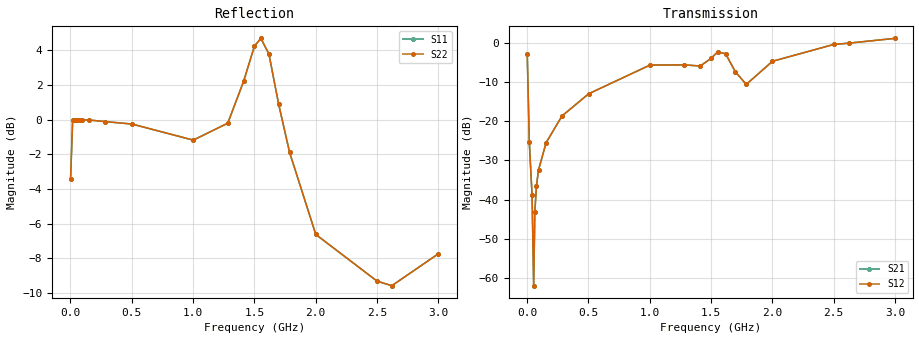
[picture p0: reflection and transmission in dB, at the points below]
!s-Parameter Generated by FASTRON Sdn. Bhd.
!FASTRON P/N : MICC-150X
!Keysight Technologies,E4991B,MY54100416,A.01.15
!Date: Fri Aug 28 11:39:31 2026
!Version  : Rev00 Fri Aug 28 11:39:31 2026
!Data & Calibration Information:
!PortZ  Port1:50+j0  Port2:50+j0
!When reading, reference impedance value at option line is always used.
! Remarks : This data is being provided solely for informational purposes.
!Freq	S11	S21	S12	S22
# Hz S dB R 50
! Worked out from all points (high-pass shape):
!   1601 points, 1 MHz to 3 GHz, reference 50 ohm
!   highest |S21| = 1.13 dB at 3 GHz (marker M1); lowest = -62.0 dB at 53.48 MHz (marker M2)
!   |S21| within 3 dB of the highest: 2.261 GHz to end of sweep
!   lowest |S11| = -9.6 dB at 2.621 GHz (marker M3), VSWR 1.99, Z = 45.6 - j33.3 ohm
!   |S11| at or under -10 dB: nowhere
!   |S22| runs from -9.6 to 4.7 dB; largest |S21 - S12| = 0
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1000000  -3.43 46.1  -2.85 -42.4  -2.85 -42.4  -3.43 46.1
1.786938e7  -0.02 3.1  -25.42 -85.9  -25.42 -85.9  -0.02 3.1
4.036188e7  -0.01 0.7  -38.88 -86.3  -38.88 -86.3  -0.01 0.7
5.34825e7  -0.01 -0.0  -61.98 20.4  -61.98 20.4  -0.01 -0.0
6.285438e7  -0.01 -0.4  -43.15 82.3  -43.15 82.3  -0.01 -0.4
7.5975e7  -0.01 -0.8  -36.62 85.6  -36.62 85.6  -0.01 -0.8
9.284438e7  -0.01 -1.4  -32.46 86.7  -32.46 86.7  -0.01 -1.4
1.546988e8  -0.02 -3.0  -25.50 85.8  -25.50 85.8  -0.02 -3.0
2.840306e8  -0.11 -6.7  -18.69 80.6  -18.69 80.6  -0.11 -6.7
5.014581e8  -0.25 -12.9  -13.02 76.3  -13.02 76.3  -0.25 -12.9
1.001916e9  -1.18 -31.3  -5.69 60.8  -5.69 60.8  -1.18 -31.3
1.283072e9  -0.20 -30.6  -5.64 72.3  -5.64 72.3  -0.20 -30.6
1.412404e9  2.22 -21.0  -5.92 114.0  -5.92 114.0  2.22 -21.0
1.5005e9  4.25 -2.6  -3.97 173.2  -3.97 173.2  4.25 -2.6
1.552982e9  4.70 11.3  -2.36 -153.8  -2.36 -153.8  4.70 11.3
1.618586e9  3.80 22.0  -2.79 -127.0  -2.79 -127.0  3.80 22.0
1.697309e9  0.92 22.7  -7.34 -93.4  -7.34 -93.4  0.92 22.7
1.787279e9  -1.89 14.1  -10.62 -41.6  -10.62 -41.6  -1.89 14.1
2.000958e9  -6.63 -19.3  -4.72 15.4  -4.72 15.4  -6.63 -19.3
2.501416e9  -9.33 -72.2  -0.42 20.0  -0.42 20.0  -9.33 -72.2
2.621376e9  -9.59 -78.4  -0.10 19.2  -0.10 19.2  -9.59 -78.4
3e9  -7.75 -99.0  1.13 20.8  1.13 20.8  -7.75 -99.0
